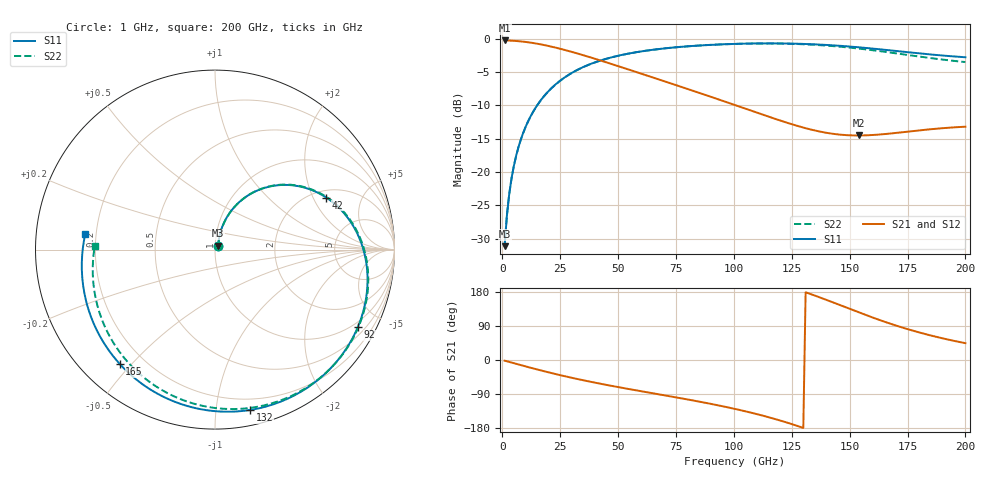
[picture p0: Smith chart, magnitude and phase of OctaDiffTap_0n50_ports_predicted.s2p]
#  Hz  S  RI  R  50
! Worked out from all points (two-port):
!   200 points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, 1 GHz to 200 GHz, reference 50 ohm
!   highest |S21| = -0.23 dB at 1 GHz (marker M1); lowest = -14.5 dB at 154 GHz (marker M2)
!   |S21| within 3 dB of the highest: start of sweep to 42.33 GHz
!   lowest |S11| = -31.1 dB at 1 GHz (marker M3), VSWR 1.06, Z = 51.7 + j2.24 ohm
!   |S11| at or under -10 dB: start of sweep to 15.01 GHz
!   |S22| runs from -31.0 to -0.7 dB; largest |S21 - S12| = 1e-08
!   S11 on the Smith chart (normalised r, x): 1 GHz: 1.03, +0.04; 42 GHz: 2.33, +2.54; 92 GHz: 0.78, -3.77; 132 GHz: 0.11, -1.23; 165 GHz: 0.11, -0.46; 200 GHz: 0.16, +0.06
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1e9  0.0174 0.0216  0.9729 -0.0289  0.9729 -0.0289  0.0183 0.0216
2e9  0.0194 0.0432  0.9709 -0.0577  0.9709 -0.0577  0.0202 0.043
4e9  0.0273 0.0856  0.9628 -0.1146  0.9628 -0.1146  0.028 0.0854
7e9  0.0485 0.1464  0.9409 -0.1972  0.9409 -0.1972  0.049 0.146
1e10  0.0799 0.2018  0.9085 -0.2745  0.9085 -0.2745  0.08 0.2013
2e10  0.2371 0.3296  0.7449 -0.477  0.7449 -0.477  0.2354 0.3298
3.5e10  0.5118 0.3414  0.4481 -0.6065  0.4481 -0.6065  0.5078 0.3455
4.2e10  0.6204 0.2896  0.3226 -0.6121  0.3226 -0.6121  0.6161 0.2965
5.5e10  0.7663 0.1381  0.1315 -0.5704  0.1315 -0.5704  0.7632 0.1506
6.8e10  0.8392 -0.052  -0.00882 -0.4934  -0.00882 -0.4934  0.8398 -0.0335
8e10  0.8457 -0.2415  -0.1024 -0.4082  -0.1024 -0.4082  0.852 -0.2181
9.2e10  0.7952 -0.4331  -0.1686 -0.3158  -0.1686 -0.3158  0.8094 -0.4058
1.01e11  0.7186 -0.5711  -0.2023 -0.2432  -0.2023 -0.2432  0.7402 -0.5422
1.16e11  0.5135 -0.7702  -0.2284 -0.1182  -0.2284 -0.1182  0.55 -0.742
1.32e11  0.1945 -0.8936  -0.2109 0.0128  -0.2109 0.0128  0.2483 -0.8734
1.34e11  0.149 -0.8994  -0.2052 0.0282  -0.2052 0.0282  0.2049 -0.8808
1.44e11  -0.0868 -0.8878  -0.1654 0.0984  -0.1654 0.0984  -0.0214 -0.8794
1.54e11  -0.3173 -0.8045  -0.1096 0.153  -0.1096 0.153  -0.2454 -0.8093
1.65e11  -0.531 -0.6366  -0.0372 0.1891  -0.0372 0.1891  -0.4564 -0.6581
1.67e11  -0.5629 -0.5993  -0.0236 0.1927  -0.0236 0.1927  -0.4884 -0.6238
1.83e11  -0.7238 -0.2622  0.0782 0.1927  0.0782 0.1927  -0.6558 -0.3096
2e11  -0.7227 0.087  0.1566 0.1532  0.1566 0.1532  -0.6693 0.0223
